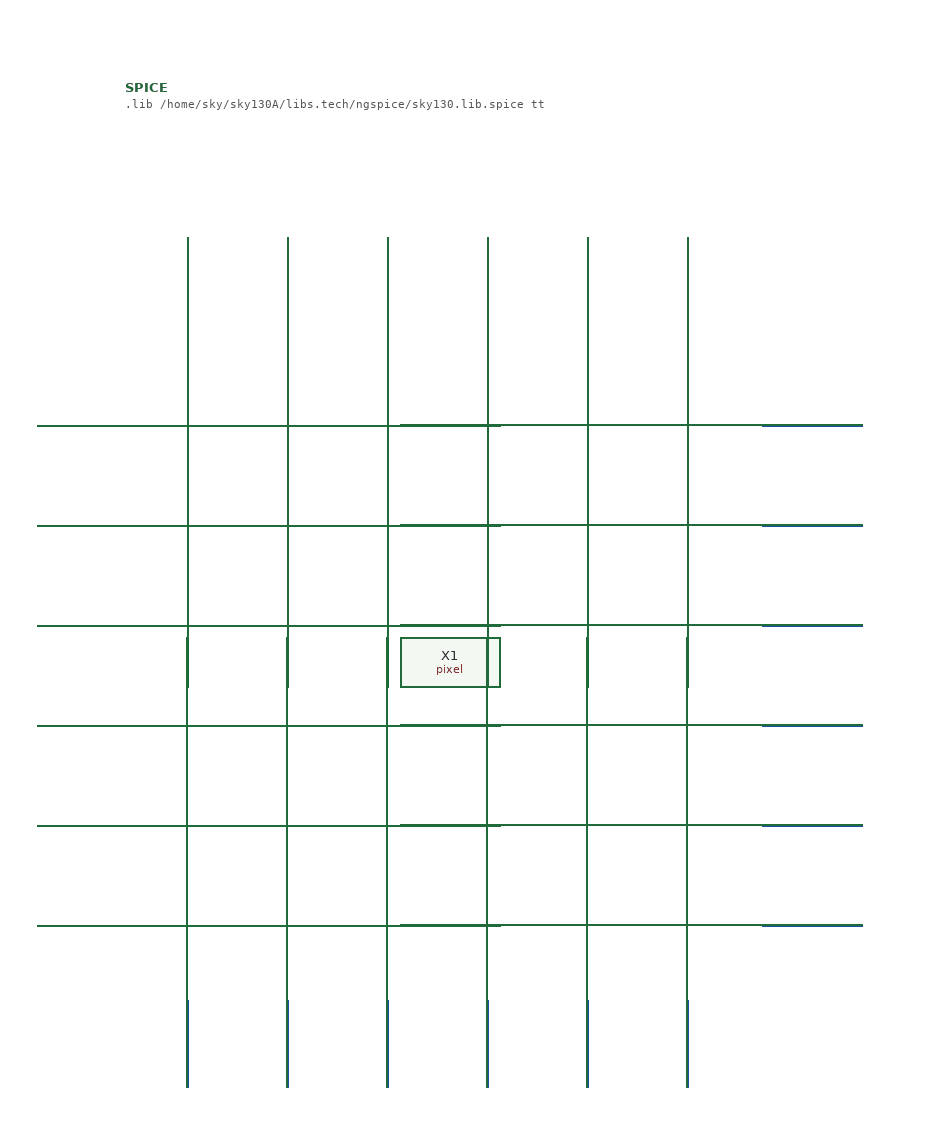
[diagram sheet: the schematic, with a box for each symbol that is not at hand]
v {xschem version=2.9.9 file_version=1.2 }
G {}
K {}
V {}
S {}
E {}
N -320 -190 -260 -190 {}
N -320 -110 -260 -110 {}
N -320 -30 -260 -30 {}
N -200 -340 -200 -250 {}
N -120 -340 -120 -250 {}
N -40 -340 -40 -250 {}
N 40 -340 40 -250 {}
N 120 -340 120 -250 {}
N 200 -340 200 -250 {}
N 260 -190 340 -190 {}
N 260 -110 340 -110 {}
N 260 -30 340 -30 {}
N 260 50 340 50 {}
N 260 130 340 130 {}
N 260 210 340 210 {}
N 200 270 200 340 {}
N 120 270 120 340 {}
N 40 270 40 340 {}
N -40 270 -40 340 {}
N -120 270 -120 340 {}
N -200 270 -200 340 {}
N -320 50 -260 50 {}
N -320 130 -260 130 {}
N -320 210 -260 210 {}
C {devices/netlist.sym} -250 -460 0 0 {name=SPICE only_toplevel=false value="
.lib /home/sky/sky130A/libs.tech/ngspice/sky130.lib.spice tt
"}
C {HW4_RAM_readout/pixel.sym} 0 10 0 0 {name=X1}
